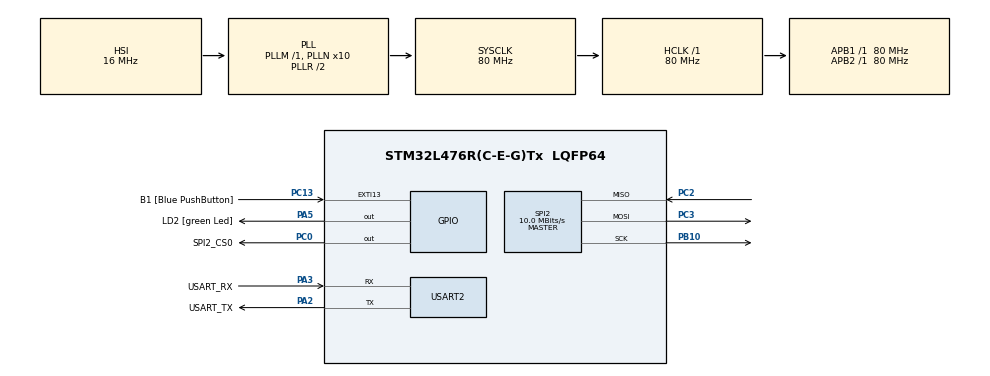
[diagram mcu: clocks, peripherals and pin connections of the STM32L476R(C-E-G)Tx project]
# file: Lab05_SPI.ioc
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Mcu.Family=STM32L4
Mcu.Name=STM32L476R(C-E-G)Tx
Mcu.Package=LQFP64
NVIC.PriorityGroup=NVIC_PRIORITYGROUP_4
PA13\ (JTMS-SWDIO).GPIO_Label=TMS
PA13\ (JTMS-SWDIO).Mode=Serial_Wire
PA13\ (JTMS-SWDIO).Signal=SYS_JTMS-SWDIO
PA14\ (JTCK-SWCLK).GPIO_Label=TCK
PA14\ (JTCK-SWCLK).Mode=Serial_Wire
PA14\ (JTCK-SWCLK).Signal=SYS_JTCK-SWCLK
PA2.GPIO_Label=USART_TX
PA2.GPIO_Mode=GPIO_MODE_AF_PP
PA2.GPIO_PuPd=GPIO_NOPULL
PA2.GPIO_Speed=GPIO_SPEED_FREQ_VERY_HIGH
PA2.Mode=Asynchronous
PA2.Signal=USART2_TX
PA3.GPIO_Label=USART_RX
PA3.GPIO_Mode=GPIO_MODE_AF_PP
PA3.GPIO_PuPd=GPIO_NOPULL
PA3.GPIO_Speed=GPIO_SPEED_FREQ_VERY_HIGH
PA3.Mode=Asynchronous
PA3.Signal=USART2_RX
PA5.GPIO_Label=LD2 [green Led]
PA5.GPIO_ModeDefaultOutputPP=GPIO_MODE_OUTPUT_PP
PA5.GPIO_PuPd=GPIO_NOPULL
PA5.GPIO_Speed=GPIO_SPEED_FREQ_LOW
PA5.Signal=GPIO_Output
PB10.Mode=Full_Duplex_Master
PB10.Signal=SPI2_SCK
PB3\ (JTDO-TRACESWO).GPIO_Label=SWO
PB3\ (JTDO-TRACESWO).Signal=SYS_JTDO-SWO
PC0.GPIO_Label=SPI2_CS0
PC0.GPIO_PuPd=GPIO_NOPULL
PC0.PinState=GPIO_PIN_SET
PC0.Signal=GPIO_Output
PC13.GPIO_Label=B1 [Blue PushButton]
PC13.GPIO_ModeDefaultEXTI=GPIO_MODE_IT_FALLING
PC13.GPIO_PuPd=GPIO_NOPULL
PC13.Signal=GPXTI13
PC14-OSC32_IN\ (PC14).Mode=LSE-External-Oscillator
PC14-OSC32_IN\ (PC14).Signal=RCC_OSC32_IN
PC15-OSC32_OUT\ (PC15).Mode=LSE-External-Oscillator
PC15-OSC32_OUT\ (PC15).Signal=RCC_OSC32_OUT
PC2.Mode=Full_Duplex_Master
PC2.Signal=SPI2_MISO
PC3.Mode=Full_Duplex_Master
PC3.Signal=SPI2_MOSI
PH0-OSC_IN\ (PH0).Signal=RCC_OSC_IN
PH1-OSC_OUT\ (PH1).Signal=RCC_OSC_OUT
ProjectManager.HeapSize=0x200
ProjectManager.StackSize=0x400
ProjectManager.TargetToolchain=STM32CubeIDE
RCC.ADCFreq_Value=64000000
RCC.AHBFreq_Value=80000000
RCC.APB1Freq_Value=80000000
RCC.APB1TimFreq_Value=80000000
RCC.APB2Freq_Value=80000000
RCC.APB2TimFreq_Value=80000000
RCC.CortexFreq_Value=80000000
RCC.HCLKFreq_Value=80000000
RCC.HSE_VALUE=8000000
RCC.HSI_VALUE=16000000
RCC.MSI_VALUE=4000000
RCC.PLLN=10
RCC.PLLSourceVirtual=RCC_PLLSOURCE_HSI
RCC.PREFETCH_ENABLE=1
RCC.SYSCLKFreq_VALUE=80000000
RCC.SYSCLKSource=RCC_SYSCLKSOURCE_PLLCLK
RCC.USBFreq_Value=64000000
RCC.VCOOutputFreq_Value=160000000
SPI2.BaudRatePrescaler=SPI_BAUDRATEPRESCALER_8
SPI2.CalculateBaudRate=10.0 MBits/s
SPI2.DataSize=SPI_DATASIZE_8BIT
SPI2.Direction=SPI_DIRECTION_2LINES
SPI2.Mode=SPI_MODE_MASTER
SPI2.VirtualType=VM_MASTER
USART2.VirtualMode-Asynchronous=VM_ASYNC
board=NUCLEO-L476RG

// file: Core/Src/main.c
/* USER CODE BEGIN Header */
/**
  ******************************************************************************
  * @file           : main.c
  * @brief          : Main program body
  ******************************************************************************
  * @attention
  *
  * Copyright (c) 2022 STMicroelectronics.
  * All rights reserved.
  *
  * This software is licensed under terms that can be found in the LICENSE file
  * in the root directory of this software component.
  * If no LICENSE file comes with this software, it is provided AS-IS.
  *
  ******************************************************************************
  */
/* USER CODE END Header */
#include "main.h"

/* USER CODE BEGIN Includes */
#include "stdio.h"
/* USER CODE END Includes */

/* USER CODE BEGIN PD */

/*EXPANDER MCP23S08 MAIN REGISTERS*/
#define IO_DIRECTION_REG 0x00
#define I_PULLUP_REG 0x06
#define I_READ_REG 0x09
#define O_CHANGE_REG 0x0A

/**/
#define EXPANDER_WRITE 0x40
#define EXPANDER_READ 0x41
/* USER CODE END PD */

 SPI_HandleTypeDef hspi2;

UART_HandleTypeDef huart2;

void SystemClock_Config(void);
static void MX_GPIO_Init(void);
static void MX_USART2_UART_Init(void);
static void MX_SPI2_Init(void);
/* USER CODE BEGIN PFP */
int _write(int file, char* message, int len)
{
	HAL_UART_Transmit(&huart2, (uint8_t*)message, len, 2);
	return len;
}

void expanderMCP_writeReg(uint8_t Reg, uint8_t Value)
{
	uint8_t tx[3] = {EXPANDER_WRITE, Reg, Value};

	HAL_GPIO_WritePin(SPI2_CS0_GPIO_Port, SPI2_CS0_Pin, GPIO_PIN_RESET);
	HAL_SPI_Transmit(&hspi2, tx, 3, HAL_MAX_DELAY);
	HAL_GPIO_WritePin(SPI2_CS0_GPIO_Port, SPI2_CS0_Pin, GPIO_PIN_SET);
}

uint8_t expanderMCP_expanderMCP_readReg(uint8_t Reg)
{
	uint8_t rx[2] = {EXPANDER_READ, Reg};
	uint8_t Value;

	HAL_GPIO_WritePin(SPI2_CS0_GPIO_Port, SPI2_CS0_Pin, GPIO_PIN_RESET);
	HAL_SPI_Transmit(&hspi2, rx, 2, HAL_MAX_DELAY);
	HAL_SPI_Receive(&hspi2, &Value, 1, HAL_MAX_DELAY);
	HAL_GPIO_WritePin(SPI2_CS0_GPIO_Port, SPI2_CS0_Pin, GPIO_PIN_SET);

	return Value;
}
/* USER CODE END PFP */

int main(void)
{

  /* MCU Configuration--------------------------------------------------------*/

  /* Reset of all peripherals, Initializes the Flash interface and the Systick. */
  HAL_Init();

  /* Configure the system clock */
  SystemClock_Config();

  /* Initialize all configured peripherals */
  MX_GPIO_Init();
  MX_USART2_UART_Init();
  MX_SPI2_Init();
  /* USER CODE BEGIN 2 */

  /*CONFIGURATING EXPANDERS GPIOS: GPIO0-GPIO3*/
  	expanderMCP_writeReg(IO_DIRECTION_REG, 0xF0);
  	uint8_t ex1[3] = {EXPANDER_WRITE, O_CHANGE_REG, 0xF5};
  	uint8_t ex2[3] = {EXPANDER_WRITE, O_CHANGE_REG, 0xFA};
  	uint8_t ex3[3] = {EXPANDER_WRITE, O_CHANGE_REG, 0xFF};
  	uint8_t ex4[3] = {EXPANDER_WRITE, O_CHANGE_REG, 0xF0};
  /* USER CODE END 2 */

  /* Infinite loop */
  /* USER CODE BEGIN WHILE */
  while (1)
  {
	  /* Zadanie na sterowanie wyjściami GPIO z expandera MCP23S08 */
	  expanderMCP_writeReg(O_CHANGE_REG, 0xF5);
	  printf("Read pins = %u", expanderMCP_readReg(I_READ_REG));
	  HAL_Delay(1000);
	  expanderMCP_writeReg(O_CHANGE_REG, 0xFA);
	  printf("Read pins = %u", expanderMCP_readReg(I_READ_REG));
	  HAL_Delay(1000);
	  expanderMCP_writeReg(O_CHANGE_REG, 0xFF);
	  printf("Read pins = %u", expanderMCP_readReg(I_READ_REG));
	  HAL_Delay(1000);
	  expanderMCP_writeReg(O_CHANGE_REG, 0xF0);
	  printf("Read pins = %u", expanderMCP_readReg(I_READ_REG));
	  HAL_Delay(1000);
    /* USER CODE END WHILE */

  }
}

void SystemClock_Config(void)
{
  RCC_OscInitTypeDef RCC_OscInitStruct = {0};
  RCC_ClkInitTypeDef RCC_ClkInitStruct = {0};

  /** Configure the main internal regulator output voltage
  */
  if (HAL_PWREx_ControlVoltageScaling(PWR_REGULATOR_VOLTAGE_SCALE1) != HAL_OK)
  {
    Error_Handler();
  }

  /** Initializes the RCC Oscillators according to the specified parameters
  * in the RCC_OscInitTypeDef structure.
  */
  RCC_OscInitStruct.OscillatorType = RCC_OSCILLATORTYPE_HSI;
  RCC_OscInitStruct.HSIState = RCC_HSI_ON;
  RCC_OscInitStruct.HSICalibrationValue = RCC_HSICALIBRATION_DEFAULT;
  RCC_OscInitStruct.PLL.PLLState = RCC_PLL_ON;
  RCC_OscInitStruct.PLL.PLLSource = RCC_PLLSOURCE_HSI;
  RCC_OscInitStruct.PLL.PLLM = 1;
  RCC_OscInitStruct.PLL.PLLN = 10;
  RCC_OscInitStruct.PLL.PLLP = RCC_PLLP_DIV7;
  RCC_OscInitStruct.PLL.PLLQ = RCC_PLLQ_DIV2;
  RCC_OscInitStruct.PLL.PLLR = RCC_PLLR_DIV2;
  if (HAL_RCC_OscConfig(&RCC_OscInitStruct) != HAL_OK)
  {
    Error_Handler();
  }

  /** Initializes the CPU, AHB and APB buses clocks
  */
  RCC_ClkInitStruct.ClockType = RCC_CLOCKTYPE_HCLK|RCC_CLOCKTYPE_SYSCLK
                              |RCC_CLOCKTYPE_PCLK1|RCC_CLOCKTYPE_PCLK2;
  RCC_ClkInitStruct.SYSCLKSource = RCC_SYSCLKSOURCE_PLLCLK;
  RCC_ClkInitStruct.AHBCLKDivider = RCC_SYSCLK_DIV1;
  RCC_ClkInitStruct.APB1CLKDivider = RCC_HCLK_DIV1;
  RCC_ClkInitStruct.APB2CLKDivider = RCC_HCLK_DIV1;

  if (HAL_RCC_ClockConfig(&RCC_ClkInitStruct, FLASH_LATENCY_4) != HAL_OK)
  {
    Error_Handler();
  }
}

static void MX_SPI2_Init(void)
{

  /* SPI2 parameter configuration*/
  hspi2.Instance = SPI2;
  hspi2.Init.Mode = SPI_MODE_MASTER;
  hspi2.Init.Direction = SPI_DIRECTION_2LINES;
  hspi2.Init.DataSize = SPI_DATASIZE_8BIT;
  hspi2.Init.CLKPolarity = SPI_POLARITY_LOW;
  hspi2.Init.CLKPhase = SPI_PHASE_1EDGE;
  hspi2.Init.NSS = SPI_NSS_SOFT;
  hspi2.Init.BaudRatePrescaler = SPI_BAUDRATEPRESCALER_8;
  hspi2.Init.FirstBit = SPI_FIRSTBIT_MSB;
  hspi2.Init.TIMode = SPI_TIMODE_DISABLE;
  hspi2.Init.CRCCalculation = SPI_CRCCALCULATION_DISABLE;
  hspi2.Init.CRCPolynomial = 7;
  hspi2.Init.CRCLength = SPI_CRC_LENGTH_DATASIZE;
  hspi2.Init.NSSPMode = SPI_NSS_PULSE_ENABLE;
  if (HAL_SPI_Init(&hspi2) != HAL_OK)
  {
    Error_Handler();
  }

}

static void MX_USART2_UART_Init(void)
{

  huart2.Instance = USART2;
  huart2.Init.BaudRate = 115200;
  huart2.Init.WordLength = UART_WORDLENGTH_8B;
  huart2.Init.StopBits = UART_STOPBITS_1;
  huart2.Init.Parity = UART_PARITY_NONE;
  huart2.Init.Mode = UART_MODE_TX_RX;
  huart2.Init.HwFlowCtl = UART_HWCONTROL_NONE;
  huart2.Init.OverSampling = UART_OVERSAMPLING_16;
  huart2.Init.OneBitSampling = UART_ONE_BIT_SAMPLE_DISABLE;
  huart2.AdvancedInit.AdvFeatureInit = UART_ADVFEATURE_NO_INIT;
  if (HAL_UART_Init(&huart2) != HAL_OK)
  {
    Error_Handler();
  }

}

static void MX_GPIO_Init(void)
{
  GPIO_InitTypeDef GPIO_InitStruct = {0};

  /* GPIO Ports Clock Enable */
  __HAL_RCC_GPIOC_CLK_ENABLE();
  __HAL_RCC_GPIOH_CLK_ENABLE();
  __HAL_RCC_GPIOA_CLK_ENABLE();
  __HAL_RCC_GPIOB_CLK_ENABLE();

  /*Configure GPIO pin Output Level */
  HAL_GPIO_WritePin(SPI2_CS0_GPIO_Port, SPI2_CS0_Pin, GPIO_PIN_SET);

  /*Configure GPIO pin Output Level */
  HAL_GPIO_WritePin(LD2_GPIO_Port, LD2_Pin, GPIO_PIN_RESET);

  /*Configure GPIO pin : B1_Pin */
  GPIO_InitStruct.Pin = B1_Pin;
  GPIO_InitStruct.Mode = GPIO_MODE_IT_FALLING;
  GPIO_InitStruct.Pull = GPIO_NOPULL;
  HAL_GPIO_Init(B1_GPIO_Port, &GPIO_InitStruct);

  /*Configure GPIO pin : SPI2_CS0_Pin */
  GPIO_InitStruct.Pin = SPI2_CS0_Pin;
  GPIO_InitStruct.Mode = GPIO_MODE_OUTPUT_PP;
  GPIO_InitStruct.Pull = GPIO_NOPULL;
  GPIO_InitStruct.Speed = GPIO_SPEED_FREQ_LOW;
  HAL_GPIO_Init(SPI2_CS0_GPIO_Port, &GPIO_InitStruct);

  /*Configure GPIO pin : LD2_Pin */
  GPIO_InitStruct.Pin = LD2_Pin;
  GPIO_InitStruct.Mode = GPIO_MODE_OUTPUT_PP;
  GPIO_InitStruct.Pull = GPIO_NOPULL;
  GPIO_InitStruct.Speed = GPIO_SPEED_FREQ_LOW;
  HAL_GPIO_Init(LD2_GPIO_Port, &GPIO_InitStruct);

  /*Configure GPIO pins : READ1_Pin READ2_Pin READ3_Pin READ4_Pin */
  GPIO_InitStruct.Pin = READ1_Pin|READ2_Pin|READ3_Pin|READ4_Pin;
  GPIO_InitStruct.Mode = GPIO_MODE_INPUT;
  GPIO_InitStruct.Pull = GPIO_PULLDOWN;
  HAL_GPIO_Init(GPIOA, &GPIO_InitStruct);

}

void Error_Handler(void)
{
  __disable_irq();
  while (1)
  {
  }
}
